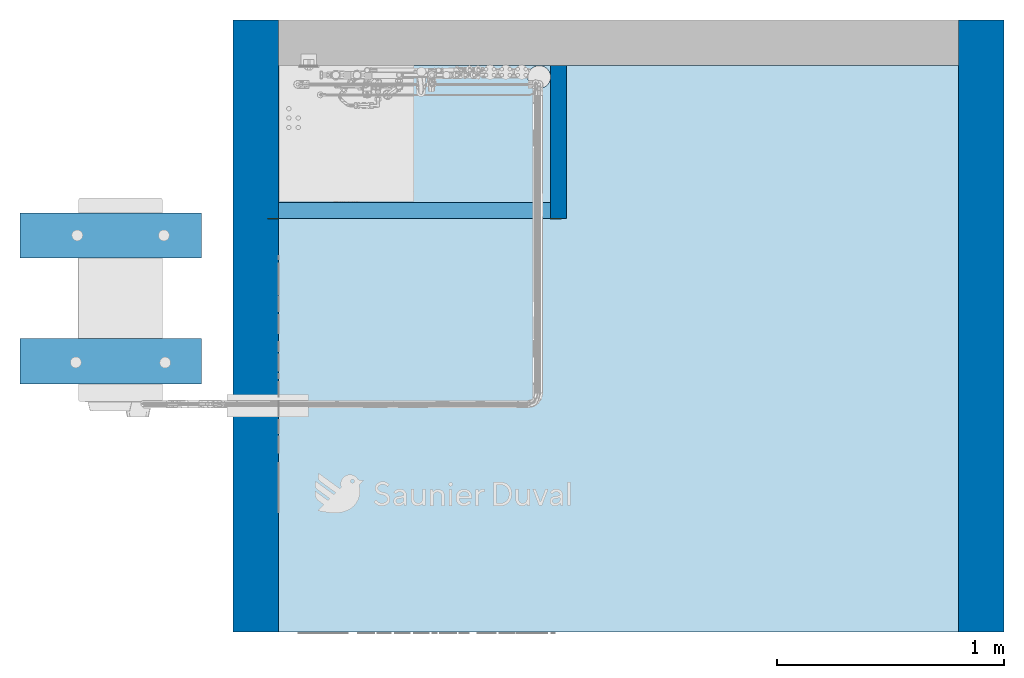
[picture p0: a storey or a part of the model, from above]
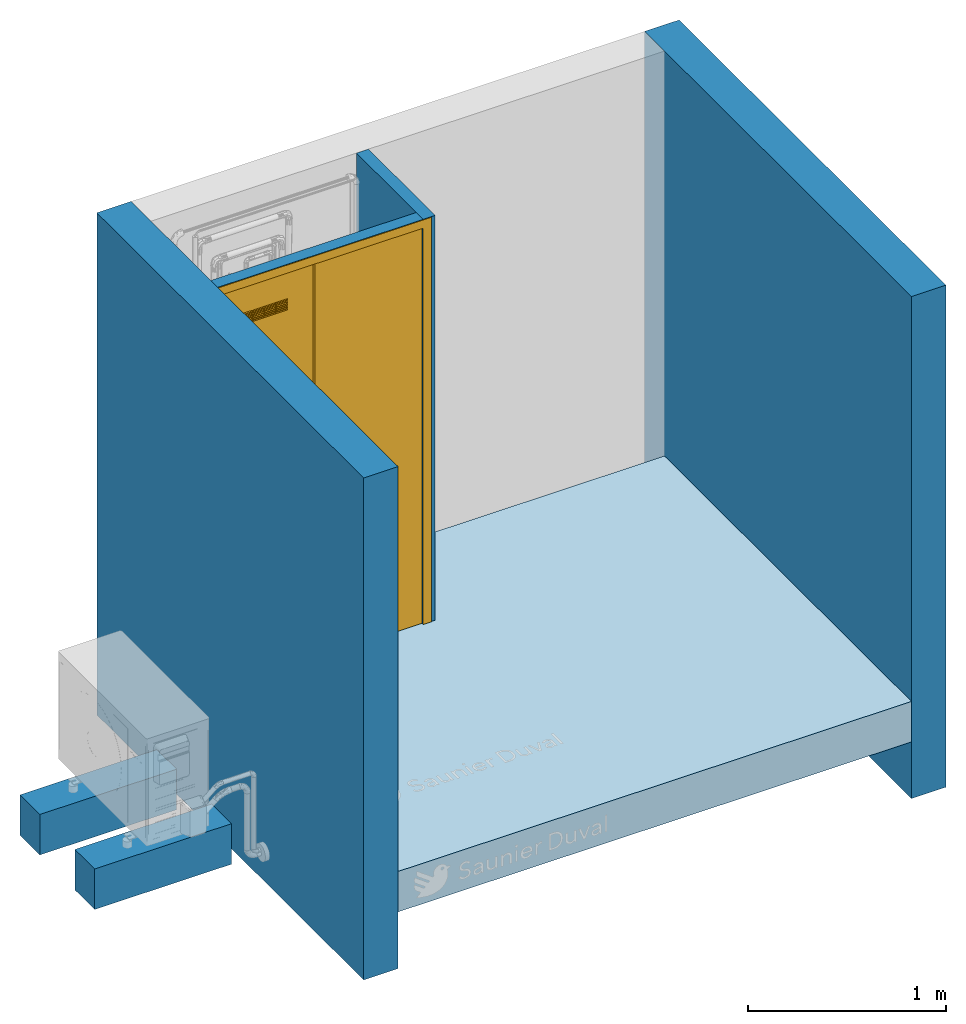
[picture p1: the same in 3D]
Properties of the parts of a building model (IFC2X3)

# File
Description: ViewDefinition [CoordinationView_V2.0], RevitIdentifiers [VersionGUID: d4a8ec76-d9b1-4843-a461-2b5db7719166, NumberOfSaves: 157], CoordinateReference [CoordinateBase: Coordonnées partagées]
File name: 0001
Time: 2024-07-11T17:51:14+01:00
Written by: ODA SDAI 24.6
Made in: Autodesk Revit 24.2.0.63 (FRA) - IFC 24.2.0.63

# IfcProject, 0001
LongName: Salle de formation PAC SD; Phase: Etat du projet

# IfcSite, Default
RefLatitude: 48, 52, 0, 117187; RefLongitude: 2, 19, 59, 880409; RefElevation: 0 m

# IfcBuilding
Pset_BuildingCommon - NumberOfStoreys: 2

# IfcBuildingStorey: Niveau:Ligne du Niveau (3)
Name | LongName | Elevation (m)
Niveau 0 | Niveau 0 | -1.94916e-14
Niveau 1 | Niveau 1 | 2.5
Niveau 2 | Niveau 2 | 6

# IfcBuildingElementProxy: Legrand Boite encastrement batibox 1 poste1:1 poste, Legrand Boite encastrement batibox 1 poste1:1 poste:1151457
In: Niveau 0
Type - Material: Plastique orange
Type - Pset_ManufacturerTypeInformation - Manufacturer: Legrand
Pset_BuildingElementProxyCommon - Reference: 1 poste; sets with these values: 2

# IfcBuildingElementProxy: Legrand Sorties de câbles:Prise courant, Legrand Sorties de câbles:Prise courant:1151456
In: Niveau 0
Type - Material: Plastique, blanc opaque, Plastique, noir opaque
Type - Pset_ManufacturerTypeInformation - Manufacturer: Legrand
Pset_BuildingElementProxyCommon - Reference: Prise courant; sets with these values: 2

# IfcBuildingElementProxy: Legrand plaque2:1 poste, Legrand plaque2:1 poste:1151458
In: Niveau 0
Type - Material: Plastique, blanc opaque
Type - Pset_ManufacturerTypeInformation - Manufacturer: Legrand
Pset_BuildingElementProxyCommon - Reference: 1 poste; sets with these values: 2

# IfcBuildingElementProxy: Legrand support universel-20181:1 poste, Legrand support universel-20181:1 poste:1151459
In: Niveau 0
Type - Material: Plastique, noir opaque
Type - Pset_ManufacturerTypeInformation - Manufacturer: Legrand
Pset_BuildingElementProxyCommon - Reference: 1 poste; sets with these values: 2

# IfcBuildingElementProxy: Logo_Geometry_SD_3Dx10-:Mur_horizontal (2)
In: Niveau 0
Type - Material: Color RGB 251-026-031, Color RGB 10-10-10
Pset_BuildingElementProxyCommon - Reference: Mur_horizontal; sets with these values: 2
Name (Logo_Geometry_SD_3Dx10-:Mur_horizontal:...)
1133916
1393715

# IfcBuildingElementProxy: Logo_Geometry_SD_3Dx10-:Sol, Logo_Geometry_SD_3Dx10-:Sol:1138120
In: Niveau 0
Type - Material: Color RGB 251-026-031, Color RGB 10-10-10
Pset_BuildingElementProxyCommon - Reference: Sol; sets with these values: 2

# IfcBuildingElementProxy: Pied antivibratile ep 40:Pied antivibratile ep 40 (4)
In: Niveau 0
Type - Material: Valeur par défaut Nouveau Matériau
Pset_BuildingElementProxyCommon - Reference: Pied antivibratile ep 40; sets with these values: 2
Name (Pied antivibratile ep 40:Pied antivibratile ep 40:...)
1088830
1088831
1088832
1088833

# IfcBuildingElementProxy: R580F:R580 3/4" x 1/2", R580F:R580 3/4" x 1/2":1107572
In: Niveau 0
Type - Material: Color RGB 169-131-7, Matériau du rendu 255-0-0
Material: <Unnamed>, Color RGB 169-131-7, Matériau du rendu 255-0-0; Group: Alimentation hydraulique 20; Alimentation hydraulique 19; Alimentation hydraulique 26; Alimentation hydraulique 25; Alimentation hydraulique 24; Alimentation hydraulique 23; Alimentation hydraulique 22; Alimentation hydraulique 16; Retour hydraulique 18; Retour hydraulique 17; Retour hydraulique 16; Retour hydraulique 15; Retour hydraulique 13; Retour hydraulique 9
Pset_BuildingElementProxyCommon - Reference: R580 3/4" x 1/2"; sets with these values: 2

# IfcCovering: Isolation des canalisations:Par défaut (32)
Type - PredefinedType: INSULATION
Material: Matériau du rendu 255-255-255
Pset_CoveringCommon - Reference: Par défaut; sets with these values: 2
Name (Isolation des canalisations:Par défaut:...) | In
1118004 | Niveau 0
1118005 | Niveau 0
1118006 | Niveau 0
1118007 | Niveau 0
1118008 | Niveau 0
1118009 | Niveau 0
1118010 | Niveau 0
1118011 | Niveau 1
1118012 | Niveau 0
1118013 | Niveau 1
1118014 | Niveau 0
1118015 | Niveau 0
1118016 | Niveau 0
1118017 | Niveau 1
1118018 | Niveau 1
1118019 | Niveau 1
1118020 | Niveau 0
1118021 | Niveau 1
1118022 | Niveau 0
1118023 | Niveau 0
1118024 | Niveau 0
1118025 | Niveau 0
1118026 | Niveau 0
1118027 | Niveau 0
1118028 | Niveau 0
1118029 | Niveau 0
1118030 | Niveau 0
1118031 | Niveau 0
1118032 | Niveau 0
1118033 | Niveau 0
1118034 | Niveau 0
1118035 | Niveau 0

# IfcDistributionPort (243)
Description: Flow
Name | FlowDirection | Group
OutPort_1088841_3 | SOURCE | Sanitaire 13
Port_1088841_4 | SOURCEANDSINK | Sanitaire 13
Port_1088842_0 | SOURCEANDSINK | Sanitaire 15
Port_1088842_1 | SOURCEANDSINK | Sanitaire 15
InPort_1088856_4 | SINK | Retour hydraulique 11
OutPort_1088861_0 | SOURCE | Retour hydraulique 11
InPort_1088888_1 | SINK | Alimentation hydraulique 15
OutPort_1088856_5 | SOURCE | Alimentation hydraulique 15
Port_1088856_6 | SOURCEANDSINK
InPort_1088861_1 | SINK | Retour hydraulique 11
OutPort_1088863_1 | SOURCE | Retour hydraulique 11
InPort_1088863_2 | SINK | Retour hydraulique 11
OutPort_1088865_0 | SOURCE | Retour hydraulique 11
InPort_1088865_1 | SINK | Retour hydraulique 11
OutPort_1115037_1 | SOURCE | Retour hydraulique 11
InPort_1115321_1 | SINK | Alimentation hydraulique 15
OutPort_1088873_0 | SOURCE | Alimentation hydraulique 15
InPort_1088873_1 | SINK | Alimentation hydraulique 15
OutPort_1088890_1 | SOURCE | Alimentation hydraulique 15
InPort_1088890_2 | SINK | Alimentation hydraulique 15
OutPort_1088888_0 | SOURCE | Alimentation hydraulique 15
Port_1088894_0 | SOURCEANDSINK | Sanitaire 19
Port_1088894_1 | SOURCEANDSINK | Sanitaire 19
Port_1089107_0 | SOURCEANDSINK | Eau Froide Sanitaire 15
Port_1089140_2 | SOURCEANDSINK | Eau Froide Sanitaire 15
Port_1089107_1 | SOURCEANDSINK | Eau Froide Sanitaire 15
Port_1089241_1 | SOURCEANDSINK | Eau Froide Sanitaire 15
Port_1089138_0 | SOURCEANDSINK | Eau Froide Sanitaire 15
Port_1089138_1 | SOURCEANDSINK | Eau Froide Sanitaire 15
Port_1089140_1 | SOURCEANDSINK | Eau Froide Sanitaire 15
Port_1089239_0 | SOURCEANDSINK | Eau Froide Sanitaire 15
Port_1089241_2 | SOURCEANDSINK | Eau Froide Sanitaire 15
Port_1089239_1 | SOURCEANDSINK | Eau Froide Sanitaire 15
Port_1101598_1 | SOURCEANDSINK | Eau Froide Sanitaire 15
InPort_1089401_0 | SINK | Eau Chaude Sanitaire 6
InPort_1089420_1 | SINK | Eau Chaude Sanitaire 6
OutPort_1089401_1 | SOURCE | Eau Chaude Sanitaire 6
InPort_1089414_0 | SINK | Eau Chaude Sanitaire 6
OutPort_1089420_2 | SOURCE | Eau Chaude Sanitaire 6
InPort_1089440_1 | SINK | Eau Chaude Sanitaire 6
OutPort_1089414_1 | SOURCE | Eau Chaude Sanitaire 6
InPort_1104246_0 | SINK | Eau Chaude Sanitaire 6
OutPort_1089440_2 | SOURCE | Eau Chaude Sanitaire 6
OutPort_1089474_0 | SOURCE | Alimentation hydraulique 20
InPort_1089474_1 | SINK | Alimentation hydraulique 20
OutPort_1089503_1 | SOURCE | Alimentation hydraulique 20
InPort_1089503_2 | SINK | Alimentation hydraulique 20
OutPort_1089497_0 | SOURCE | Alimentation hydraulique 20
InPort_1089497_1 | SINK | Alimentation hydraulique 20
OutPort_1108240_1 | SOURCE | Alimentation hydraulique 20
InPort_1108240_2 | SINK | Alimentation hydraulique 20
OutPort_1089513_0 | SOURCE | Alimentation hydraulique 20
InPort_1089513_1 | SINK | Alimentation hydraulique 20
OutPort_1108242_2 | SOURCE | Alimentation hydraulique 20
OutPort_1089553_0 | SOURCE | Retour hydraulique 14
InPort_1089553_1 | SINK | Retour hydraulique 14
OutPort_1089572_1 | SOURCE | Retour hydraulique 14
InPort_1089572_2 | SINK | Retour hydraulique 14
OutPort_1089566_0 | SOURCE | Retour hydraulique 14
InPort_1089566_1 | SINK | Retour hydraulique 14
OutPort_1108389_1 | SOURCE | Retour hydraulique 14
OutPort_1098783_2 | SOURCE
InPort_1098783_5 | SINK | Eau Froide Sanitaire 15
OutPort_1099300_2 | SOURCE | Eau Froide Sanitaire 15
InPort_1099504_0 | SINK | Eau Froide Sanitaire 16
OutPort_1098783_6 | SOURCE | Eau Froide Sanitaire 16
InPort_1099460_0 | SINK | Eau Froide Sanitaire 14
OutPort_1098783_7 | SOURCE | Eau Froide Sanitaire 14
InPort_1099562_0 | SINK | Eau Froide Sanitaire 17
OutPort_1098783_8 | SOURCE | Eau Froide Sanitaire 17
InPort_1099265_0 | SINK | Eau Froide Sanitaire 15
OutPort_1101598_2 | SOURCE | Eau Froide Sanitaire 15
InPort_1099300_1 | SINK | Eau Froide Sanitaire 15
OutPort_1099265_1 | SOURCE | Eau Froide Sanitaire 15
OutPort_1099460_1 | SOURCE | Eau Froide Sanitaire 14
OutPort_1099504_1 | SOURCE | Eau Froide Sanitaire 16
OutPort_1099562_1 | SOURCE | Eau Froide Sanitaire 17
OutPort_1099806_2 | SOURCE
InPort_1099806_5 | SINK | Eau Chaude Sanitaire 6
OutPort_1104268_1 | SOURCE | Eau Chaude Sanitaire 6
OutPort_1099806_6 | SOURCE
InPort_1100829_0 | SINK | Eau Chaude Sanitaire 4
OutPort_1099806_7 | SOURCE | Eau Chaude Sanitaire 4
InPort_1100867_0 | SINK | Eau Chaude Sanitaire 7
OutPort_1099806_8 | SOURCE | Eau Chaude Sanitaire 7
OutPort_1100829_1 | SOURCE | Eau Chaude Sanitaire 4
OutPort_1100867_1 | SOURCE | Eau Chaude Sanitaire 7
InPort_1101598_3 | SINK | Eau Froide Sanitaire 15
OutPort_1102837_0 | SOURCE | Eau Froide Sanitaire 15
InPort_1102572_1 | SINK | Eau Froide Sanitaire 15
OutPort_1101707_0 | SOURCE | Eau Froide Sanitaire 15
InPort_1101707_1 | SINK | Eau Froide Sanitaire 15
InPort_1102590_1 | SINK | Eau Froide Sanitaire 15
OutPort_1102572_2 | SOURCE | Eau Froide Sanitaire 15
InPort_1102797_1 | SINK | Eau Froide Sanitaire 15
OutPort_1102590_0 | SOURCE | Eau Froide Sanitaire 15
InPort_1102837_1 | SINK | Eau Froide Sanitaire 15
OutPort_1102797_2 | SOURCE | Eau Froide Sanitaire 15
InPort_1104285_1 | SINK | Eau Chaude Sanitaire 6
OutPort_1104246_1 | SOURCE | Eau Chaude Sanitaire 6
InPort_1104268_2 | SINK | Eau Chaude Sanitaire 6
OutPort_1104256_0 | SOURCE | Eau Chaude Sanitaire 6
InPort_1104256_1 | SINK | Eau Chaude Sanitaire 6
OutPort_1104285_2 | SOURCE | Eau Chaude Sanitaire 6
InPort_1107572_1 | SINK | Alimentation hydraulique 19
OutPort_1108148_1 | SOURCE | Alimentation hydraulique 19
InPort_1108068_1 | SINK | Alimentation hydraulique 20
OutPort_1107572_2 | SOURCE | Alimentation hydraulique 20
InPort_1109853_0 | SINK | Alimentation hydraulique 26
OutPort_1107572_3 | SOURCE | Alimentation hydraulique 26
InPort_1109774_0 | SINK | Alimentation hydraulique 25
OutPort_1107572_4 | SOURCE | Alimentation hydraulique 25
InPort_1109692_0 | SINK | Alimentation hydraulique 24
OutPort_1107572_5 | SOURCE | Alimentation hydraulique 24
InPort_1109607_0 | SINK | Alimentation hydraulique 23
OutPort_1107572_6 | SOURCE | Alimentation hydraulique 23
InPort_1109531_0 | SINK | Alimentation hydraulique 22
OutPort_1107572_7 | SOURCE | Alimentation hydraulique 22
InPort_1109451_0 | SINK | Alimentation hydraulique 16
OutPort_1107572_8 | SOURCE | Alimentation hydraulique 16
InPort_1107572_9 | SINK | Retour hydraulique 18
OutPort_1109369_0 | SOURCE | Retour hydraulique 18
InPort_1107572_10 | SINK | Retour hydraulique 17
OutPort_1109291_0 | SOURCE | Retour hydraulique 17
InPort_1107572_11 | SINK | Retour hydraulique 16
OutPort_1109175_0 | SOURCE | Retour hydraulique 16
InPort_1107572_12 | SINK | Retour hydraulique 15
OutPort_1109048_0 | SOURCE | Retour hydraulique 15
InPort_1107572_13 | SINK | Retour hydraulique 13
OutPort_1108907_0 | SOURCE | Retour hydraulique 13
InPort_1107572_14 | SINK | Retour hydraulique 9
OutPort_1108758_0 | SOURCE | Retour hydraulique 9
InPort_1108389_2 | SINK | Retour hydraulique 14
OutPort_1108037_0 | SOURCE | Retour hydraulique 14
InPort_1108037_1 | SINK | Retour hydraulique 14
OutPort_1108391_2 | SOURCE | Retour hydraulique 14
InPort_1108058_0 | SINK | Alimentation hydraulique 20
OutPort_1108068_2 | SOURCE | Alimentation hydraulique 20
InPort_1108242_1 | SINK | Alimentation hydraulique 20
OutPort_1108058_1 | SOURCE | Alimentation hydraulique 20
InPort_1108148_1 | SINK | Alimentation hydraulique 19
OutPort_1107572_1 | SOURCE | Alimentation hydraulique 19
InPort_1108306_0 | SINK | Alimentation hydraulique 19
OutPort_1108148_2 | SOURCE | Alimentation hydraulique 19
InPort_1108391_1 | SINK | Retour hydraulique 14
OutPort_1108306_1 | SOURCE | Retour hydraulique 14
InPort_1108758_1 | SINK | Retour hydraulique 9
InPort_1108907_1 | SINK | Retour hydraulique 13
InPort_1109048_1 | SINK | Retour hydraulique 15
InPort_1109175_1 | SINK | Retour hydraulique 16
InPort_1109291_1 | SINK | Retour hydraulique 17
InPort_1109369_1 | SINK | Retour hydraulique 18
OutPort_1109451_1 | SOURCE | Alimentation hydraulique 16
OutPort_1109531_1 | SOURCE | Alimentation hydraulique 22
OutPort_1109607_1 | SOURCE | Alimentation hydraulique 23
OutPort_1109692_1 | SOURCE | Alimentation hydraulique 24
OutPort_1109774_1 | SOURCE | Alimentation hydraulique 25
OutPort_1109853_1 | SOURCE | Alimentation hydraulique 26
Port_1110453_0 | SOURCEANDSINK | Alimentation hydraulique 27
Port_1110453_1 | SOURCEANDSINK | Alimentation hydraulique 27
InPort_1114524_0 | SINK | Alimentation hydraulique 21
InPort_1114792_1 | SINK | Alimentation hydraulique 21
OutPort_1114524_1 | SOURCE | Alimentation hydraulique 21
InPort_1114532_0 | SINK | Alimentation hydraulique 21
OutPort_1114792_2 | SOURCE | Alimentation hydraulique 21
InPort_1114834_1 | SINK | Alimentation hydraulique 21
OutPort_1114532_1 | SOURCE | Alimentation hydraulique 21
OutPort_1114585_0 | SOURCE | Sanitaire 17
InPort_1114585_1 | SINK | Sanitaire 17
OutPort_1114601_1 | SOURCE | Sanitaire 17
InPort_1114601_2 | SINK | Sanitaire 17
OutPort_1114595_0 | SOURCE | Sanitaire 17
InPort_1114595_1 | SINK | Alimentation hydraulique 15
OutPort_1114614_1 | SOURCE | Alimentation hydraulique 15
InPort_1114614_2 | SINK | Alimentation hydraulique 15
OutPort_1114606_0 | SOURCE | Alimentation hydraulique 15
InPort_1114606_1 | SINK | Alimentation hydraulique 15
OutPort_1115197_1 | SOURCE | Alimentation hydraulique 15
InPort_1114860_0 | SINK | Alimentation hydraulique 21
OutPort_1114834_2 | SOURCE | Alimentation hydraulique 21
InPort_1114878_1 | SINK | Alimentation hydraulique 21
OutPort_1114860_1 | SOURCE | Alimentation hydraulique 21
InPort_1114870_0 | SINK | Alimentation hydraulique 21
OutPort_1114878_2 | SOURCE | Alimentation hydraulique 21
InPort_1114887_1 | SINK | Alimentation hydraulique 21
OutPort_1114870_1 | SOURCE | Alimentation hydraulique 21
InPort_1114881_0 | SINK | Alimentation hydraulique 21
OutPort_1114887_2 | SOURCE | Alimentation hydraulique 21
InPort_1115096_2 | SINK | Alimentation hydraulique 21
OutPort_1114881_1 | SOURCE | Alimentation hydraulique 21
InPort_1115037_2 | SINK | Retour hydraulique 11
OutPort_1115029_0 | SOURCE | Retour hydraulique 11
InPort_1115029_1 | SINK | Alimentation hydraulique 21
OutPort_1115098_1 | SOURCE | Alimentation hydraulique 21
InPort_1115042_0 | SINK | Alimentation hydraulique 21
OutPort_1115096_1 | SOURCE | Alimentation hydraulique 21
InPort_1115098_2 | SINK | Alimentation hydraulique 21
OutPort_1115042_1 | SOURCE | Alimentation hydraulique 21
InPort_1115197_2 | SINK | Alimentation hydraulique 15
OutPort_1115185_0 | SOURCE | Alimentation hydraulique 15
InPort_1115185_1 | SINK | Alimentation hydraulique 15
OutPort_1115335_2 | SOURCE | Alimentation hydraulique 15
InPort_1115223_0 | SINK | Alimentation hydraulique 15
OutPort_1115331_2 | SOURCE | Alimentation hydraulique 15
InPort_1115335_1 | SINK | Alimentation hydraulique 15
OutPort_1115223_1 | SOURCE | Alimentation hydraulique 15
InPort_1115310_0 | SINK | Alimentation hydraulique 15
OutPort_1115321_2 | SOURCE | Alimentation hydraulique 15
InPort_1115331_1 | SINK | Alimentation hydraulique 15
OutPort_1115310_1 | SOURCE | Alimentation hydraulique 15
Port_1115904_0 | SOURCEANDSINK | Alimentation hydraulique 28
Port_1115904_1 | SOURCEANDSINK | Alimentation hydraulique 28
Port_1117079_0 | SOURCEANDSINK | Alimentation hydraulique 29
Port_1117079_1 | SOURCEANDSINK | Alimentation hydraulique 29
Port_1117090_0 | SOURCEANDSINK | Alimentation hydraulique 30
Port_1117090_1 | SOURCEANDSINK | Alimentation hydraulique 30
Port_1117101_0 | SOURCEANDSINK | Alimentation hydraulique 31
Port_1117101_1 | SOURCEANDSINK | Alimentation hydraulique 31
Port_1117112_0 | SOURCEANDSINK | Alimentation hydraulique 32
Port_1117112_1 | SOURCEANDSINK | Alimentation hydraulique 32
Port_1117125_0 | SOURCEANDSINK | Alimentation hydraulique 33
Port_1117125_1 | SOURCEANDSINK | Alimentation hydraulique 33
Port_1117146_0 | SOURCEANDSINK | Alimentation hydraulique 34
Port_1117146_1 | SOURCEANDSINK | Alimentation hydraulique 34
Port_1117281_0 | SOURCEANDSINK | Alimentation hydraulique 35
Port_1117281_1 | SOURCEANDSINK | Alimentation hydraulique 35
Port_1117298_0 | SOURCEANDSINK | Alimentation hydraulique 36
Port_1117298_1 | SOURCEANDSINK | Alimentation hydraulique 36
Port_1117587_0 | SOURCEANDSINK | Alimentation hydraulique 37
Port_1117587_1 | SOURCEANDSINK | Alimentation hydraulique 37
InPort_1120506_10 | SINK
OutPort_1120506_11 | SOURCE
OutPort_1120506_16 | SOURCE
OutPort_1120506_17 | SOURCE
InPort_1120506_18 | SINK
OutPort_1120506_19 | SOURCE
InPort_1120506_20 | SINK
OutPort_1120506_21 | SOURCE
InPort_1120506_22 | SINK
InPort_1120506_23 | SINK
OutPort_1120506_24 | SOURCE
OutPort_1120506_25 | SOURCE
Port_1120506_26 | SOURCEANDSINK

# IfcDoor: Placard coulissante - 2 panneaux_GM:Placard coulissante - 2 panneaux 2.50, Placard coulissante - 2 panneaux_GM:Placard coulissante - 2 panneaux 2.50:1122378
In: Niveau 0
Type - OperationType: SLIDING_TO_RIGHT; ParameterTakesPrecedence: no; Sizeable: no; Material: Plastique, blanc opaque, Verre, vitrage transparent
Type - Placard coulissante - 2 panneaux_GM:Placard coulissante - 2 panneaux 2.50:1122378:1 - PanelOperation: SLIDING
Type - Pset_DoorCommon - IsExternal: no; ThermalTransmittance: 3.7021 kg/K/s3
OverallHeight: 2.45 m; OverallWidth: 1.2 m
Pset_DoorCommon - Reference: Placard coulissante - 2 panneaux 2.50
Pset_QuantityTakeOff - Reference: Placard coulissante - 2 panneaux 2.50

# IfcFlowController: HC_Manifold_MEPcontent_Valsir_Pexal BRASS_3 Way Cold Water_INT-EN:1/2'' x 3/4'', HC_Manifold_MEPcontent_Valsir_Pexal BRASS_3 Way Cold Water_INT-EN:1/2'' x 3/4'':1098783
In: Niveau 0
Type - Material: Color RGB 202-154-058
Type - Pset_ElementShading - Color: Color RGB 202-154-058
Type - Pset_ManufacturerTypeInformation - Manufacturer: Valsir S.p.A.
Classification: SfB]53 (Default Classification); Group: Eau Froide Sanitaire 15; Eau Froide Sanitaire 16; Eau Froide Sanitaire 14; Eau Froide Sanitaire 17
Pset_DistributionFlowElementCommon - Reference: 1/2'' x 3/4''; sets with these values: 2

# IfcFlowController: HC_Manifold_MEPcontent_Valsir_Pexal BRASS_3 Way Hot Water_INT-EN:1/2'' x 3/4'', HC_Manifold_MEPcontent_Valsir_Pexal BRASS_3 Way Hot Water_INT-EN:1/2'' x 3/4'':1099806
In: Niveau 0
Type - Material: Color RGB 202-154-058
Type - Pset_ElementShading - Color: Color RGB 202-154-058
Type - Pset_ManufacturerTypeInformation - Manufacturer: Valsir S.p.A.
Classification: SfB]53 (Default Classification); Group: Eau Chaude Sanitaire 6; Eau Chaude Sanitaire 4; Eau Chaude Sanitaire 7
Pset_DistributionFlowElementCommon - Reference: 1/2'' x 3/4''; sets with these values: 2

# IfcFlowController: M_Valve_Ball_MEPcontent_Caleffi_327 DN20:3/4'', M_Valve_Ball_MEPcontent_Caleffi_327 DN20:3/4'':1102572
In: Niveau 0
Type - PredefinedType: REGULATING; Material: Color RGB 187-001-001, Color RGB 202-154-058, Color RGB 045-045-045
Type - Pset_DuctConnection - ConnectionType: Gas ISO 228/1
Type - Pset_ManufacturerTypeInformation - Manufacturer: Caleffi Italy
Type - Pset_PipeConnection - ConnectionType: Gas ISO 228/1
Material: Color RGB 045-045-045, Color RGB 202-154-058, Color RGB 187-001-001; Group: Eau Froide Sanitaire 15
Pset_DistributionFlowElementCommon - Reference: 3/4''; sets with these values: 2

# IfcFlowController: Plumbing_Valves_Caleffi_Pressure_ Reducing_ Valve-533HA-DN15_DN20:533340HA, Plumbing_Valves_Caleffi_Pressure_ Reducing_ Valve-533HA-DN15_DN20:533340HA:1102797
In: Niveau 0
Type - Material: Metal - Caleffi - Brass, Technopolymer - Caleffi - Black, Technopolymer - Caleffi - Grey
Type - Pset_DuctConnection - ConnectionType: NPT
Type - Pset_ManufacturerTypeInformation - Manufacturer: Caleffi North America, Inc.
Type - Pset_PipeConnection - ConnectionType: NPT
Classification: D3040 Uniformat (Uniformat); Group: Eau Froide Sanitaire 15
Pset_DistributionFlowElementCommon - Reference: 533340HA; sets with these values: 2

# IfcFlowController: Siphon 32:Siphon 32, Siphon 32:Siphon 32:1088841
In: Niveau 0
Type - Material: <Unnamed>
Type - Pset_ManufacturerTypeInformation - Manufacturer: GIRPI
Pset_DistributionFlowElementCommon - Reference: Siphon 32; sets with these values: 2
Group: Sanitaire 13

# IfcFlowFitting: COMAP - SKINPRESS ppsu - Coude_45_90_9041W_9090W:Coude_45_90_9041W_9090W (11)
In: Niveau 0
Type - Material: PPSU, Bague blanche VisuControl, Inox
Type - Pset_ManufacturerTypeInformation - Manufacturer: COMAP
Pset_DistributionFlowElementCommon - Reference: Coude_45_90_9041W_9090W; sets with these values: 2
Name (COMAP - SKINPRESS ppsu - Coude_45_90_9041W_9090W:Coude_45_90_9041W_9090W:...) | Group | Material
1089140 | Eau Froide Sanitaire 15
1089241 | Eau Froide Sanitaire 15 | Bague blanche VisuControl, Inox, PPSU
1089420 | Eau Chaude Sanitaire 6 | Bague blanche VisuControl, Inox, PPSU
1089440 | Eau Chaude Sanitaire 6 | Bague blanche VisuControl, Inox, PPSU
1089503 | Alimentation hydraulique 20
1089572 | Retour hydraulique 14 | Bague blanche VisuControl, Inox, PPSU
1104285 | Eau Chaude Sanitaire 6 | Bague blanche VisuControl, Inox, PPSU
1108240 | Alimentation hydraulique 20 | Bague blanche VisuControl, Inox, PPSU
1108242 | Alimentation hydraulique 20 | Bague blanche VisuControl, Inox, PPSU
1108389 | Retour hydraulique 14 | Bague blanche VisuControl, Inox, PPSU
1108391 | Retour hydraulique 14 | Bague blanche VisuControl, Inox, PPSU

# IfcFlowFitting: COMAP - SKINPRESS ppsu - Manchon_Réduit_9240W:Manchon_Réduit_9240W (4)
In: Niveau 0
Type - Material: Bague blanche VisuControl, Inox, PPSU
Type - Pset_ManufacturerTypeInformation - Manufacturer: COMAP
Pset_DistributionFlowElementCommon - Reference: Manchon_Réduit_9240W; sets with these values: 2
Name (COMAP - SKINPRESS ppsu - Manchon_Réduit_9240W:Manchon_Réduit_9240W:...) | Group
1099300 | Eau Froide Sanitaire 15
1104268 | Eau Chaude Sanitaire 6
1108068 | Alimentation hydraulique 20
1108148 | Alimentation hydraulique 19

# IfcFlowFitting: COMAP - SKINPRESS ppsu - Té_égal_réduit_9130W_9130RW:Standard, COMAP - SKINPRESS ppsu - Té_égal_réduit_9130W_9130RW:Standard:1101598
In: Niveau 0
Type - Material: Bague blanche VisuControl, Inox, PPSU
Type - Pset_ManufacturerTypeInformation - Manufacturer: COMAP
Pset_DistributionFlowElementCommon - Reference: Standard; sets with these values: 2
Group: Eau Froide Sanitaire 15

# IfcFlowFitting: Coude - tube frigo:Standard (15)
In: Niveau 0
Type - Material: Cuivre
Pset_DistributionFlowElementCommon - Reference: Standard; sets with these values: 2
Name (Coude - tube frigo:Standard:...) | Group
1088863 | Retour hydraulique 11
1088890 | Alimentation hydraulique 15
1114601 | Sanitaire 17
1114614 | Alimentation hydraulique 15
1114792 | Alimentation hydraulique 21
1114834 | Alimentation hydraulique 21
1114878 | Alimentation hydraulique 21
1114887 | Alimentation hydraulique 21
1115037 | Retour hydraulique 11
1115096 | Alimentation hydraulique 21
1115098 | Alimentation hydraulique 21
1115197 | Alimentation hydraulique 15
1115321 | Alimentation hydraulique 15
1115331 | Alimentation hydraulique 15
1115335 | Alimentation hydraulique 15

# IfcFlowFitting: SA_Connection Piece_MEPcontent_Valsir_Pexal BRASS_Kit with Nut_Shared:14 mm x 2 mm-1/2'' (6)
In: Niveau 0
Type - Material: Color RGB 202-154-058
Type - Pset_ElementShading - Color: Color RGB 202-154-058
Type - Pset_FlowFittingDuctFitting - Color: Color RGB 202-154-058
Type - Pset_FlowFittingPipeFitting - Color: Color RGB 202-154-058
Type - Pset_ManufacturerTypeInformation - Manufacturer: Valsir S.p.A.
Classification: SfB]53 (Default Classification)
Pset_DistributionFlowElementCommon - Reference: 14 mm x 2 mm-1/2''; sets with these values: 2
Name (SA_Connection Piece_MEPcontent_Valsir_Pexal BRASS_Kit with Nut_Shared:14 mm x 2 mm-1/2'':...)
1098784
1098785
1098786
1099807
1099808
1099809

# IfcFlowMovingDevice: HC_Heat Pump_GM_Saunier Duval_GeniaSet TEK_IS_kit complet+2C:HA 10-7_2 STB, HC_Heat Pump_GM_Saunier Duval_GeniaSet TEK_IS_kit complet+2C:HA 10-7_2 STB:1120506
In: Niveau 0
Type - Material: Color RGB 121-121-121, Color RGB 244-244-244, Color RGB 116-051-029, Color RGB 040-040-040, Color RGB 251-026-031, Color RGB 191-153-066
Type - Pset_ManufacturerTypeInformation - Manufacturer: Saunier Duval
Material: Color RGB 191-153-066, Color RGB 040-040-040, Color RGB 000-000-255, Color RGB 116-051-029, <Unnamed>, Color RGB 120-120-120, Color RGB 251-026-031, Color RGB 121-121-121, Color RGB 244-244-244
Pset_DistributionFlowElementCommon - Reference: HA 10-7_2 STB; sets with these values: 2

# IfcFlowMovingDevice: HC_Heat Pump_MEPcontent_Saunier Duval_GeniaAir TEK_HA 4-6_FR-FR:HA 4-7_2 OS 230V B3, HC_Heat Pump_MEPcontent_Saunier Duval_GeniaAir TEK_HA 4-6_FR-FR:HA 4-7_2 OS 230V B3:1088856
In: Niveau 0
Type - Material: Color RGB 040-040-040, Color RGB 251-026-031, Color RGB 235-235-235, Color RGB 190-190-190, Color RGB 174-174-174
Type - Pset_ManufacturerTypeInformation - Manufacturer: Saunier Duval
Pset_DistributionFlowElementCommon - Reference: HA 4-7_2 OS 230V B3; sets with these values: 2
Group: Retour hydraulique 11; Alimentation hydraulique 15

# IfcFlowSegment: Canalisation souple arrondie:Souple - Circulaire, Canalisation souple arrondie:Souple - Circulaire:1088894
In: Niveau 0
Type - PredefinedType: FLEXIBLESEGMENT
Pset_DistributionFlowElementCommon - Reference: Souple - Circulaire; sets with these values: 2
Group: Sanitaire 19

# IfcFlowSegment: Canalisation:COMAP MULTISKIN - SKINPRESS PPSU (24)
In: Niveau 0
Type - Pset_ManufacturerTypeInformation - Manufacturer: COMAP
Pset_DistributionFlowElementCommon - Reference: COMAP MULTISKIN - SKINPRESS PPSU; sets with these values: 2
Pset_FlowSegmentDuctSegment - sets with these values: 2
Name (Canalisation:COMAP MULTISKIN - SKINPRESS PPSU:...) | Length (m) | Group
1089107 | 0.105 | Eau Froide Sanitaire 15
1089138 | 0.0634913 | Eau Froide Sanitaire 15
1089239 | 1.76 | Eau Froide Sanitaire 15
1089401 | 0.1475 | Eau Chaude Sanitaire 6
1089414 | 0.275 | Eau Chaude Sanitaire 6
1089474 | 0.101544 | Alimentation hydraulique 20
1089497 | 0.319 | Alimentation hydraulique 20
1089513 | 1.61979 | Alimentation hydraulique 20
1089553 | 0.247 | Retour hydraulique 14
1089566 | 0.4515 | Retour hydraulique 14
1099265 | 0.0579708 | Eau Froide Sanitaire 15
1099460 | 0.6016 | Eau Froide Sanitaire 14
1099504 | 0.6016 | Eau Froide Sanitaire 16
1099562 | 0.6 | Eau Froide Sanitaire 17
1100829 | 0.6516 | Eau Chaude Sanitaire 4
1100867 | 0.65 | Eau Chaude Sanitaire 7
1101707 | 0.353 | Eau Froide Sanitaire 15
1102590 | 0.02975 | Eau Froide Sanitaire 15
1102837 | 0.05325 | Eau Froide Sanitaire 15
1104246 | 1.74141 | Eau Chaude Sanitaire 6
1104256 | 0.0478441 | Eau Chaude Sanitaire 6
1108037 | 1.64869 | Retour hydraulique 14
1108058 | 0.1005 | Alimentation hydraulique 20
1108306 | 0.061 | Retour hydraulique 14; Alimentation hydraulique 19

# IfcFlowSegment: Canalisation:Cuivre Frigo (17)
In: Niveau 0
Pset_DistributionFlowElementCommon - Reference: Cuivre Frigo; sets with these values: 2
Pset_FlowSegmentDuctSegment - sets with these values: 2
Name (Canalisation:Cuivre Frigo:...) | Length (m) | Group
1088861 | 0.1455 | Retour hydraulique 11
1088865 | 0.159449 | Retour hydraulique 11
1088873 | 0.0496756 | Alimentation hydraulique 15
1088888 | 0.137924 | Alimentation hydraulique 15
1114524 | 0.4909 | Alimentation hydraulique 21
1114532 | 0.9018 | Alimentation hydraulique 21
1114585 | 0.440138 | Sanitaire 17
1114595 | 0.9664 | Alimentation hydraulique 15; Sanitaire 17
1114606 | 2.75084 | Alimentation hydraulique 15
1114860 | 0.0043 | Alimentation hydraulique 21
1114870 | 2.7968 | Alimentation hydraulique 21
1114881 | 1.36677 | Alimentation hydraulique 21
1115029 | 0.445144 | Retour hydraulique 11; Alimentation hydraulique 21
1115042 | 1.34742 | Alimentation hydraulique 21
1115185 | 1.31187 | Alimentation hydraulique 15
1115223 | 1.35145 | Alimentation hydraulique 15
1115310 | 0.352103 | Alimentation hydraulique 15

# IfcFlowSegment: Canalisation:PER Bleu (6)
In: Niveau 0
Pset_DistributionFlowElementCommon - Reference: PER Bleu; sets with these values: 2
Pset_FlowSegmentDuctSegment - sets with these values: 2
Name (Canalisation:PER Bleu:...) | Length (m) | Group
1108758 | 0.596336 | Retour hydraulique 9
1108907 | 0.595 | Retour hydraulique 13
1109048 | 0.595 | Retour hydraulique 15
1109175 | 0.596336 | Retour hydraulique 16
1109291 | 0.596336 | Retour hydraulique 17
1109369 | 0.596336 | Retour hydraulique 18

# IfcFlowSegment: Canalisation:PER Rouge (6)
In: Niveau 0
Pset_DistributionFlowElementCommon - Reference: PER Rouge; sets with these values: 2
Pset_FlowSegmentDuctSegment - sets with these values: 2
Name (Canalisation:PER Rouge:...) | Length (m) | Group
1109451 | 0.577034 | Alimentation hydraulique 16
1109531 | 0.577034 | Alimentation hydraulique 22
1109607 | 0.595606 | Alimentation hydraulique 23
1109692 | 0.595606 | Alimentation hydraulique 24
1109774 | 0.595606 | Alimentation hydraulique 25
1109853 | 0.595606 | Alimentation hydraulique 26

# IfcFlowSegment: Canalisation:PVC - NF (12)
In: Niveau 0
Pset_DistributionFlowElementCommon - Reference: PVC - NF; sets with these values: 2
Pset_FlowSegmentDuctSegment - sets with these values: 2
Name (Canalisation:PVC - NF:...) | Length (m) | Group
1088842 | 0.35 | Sanitaire 15
1110453 | 0.365 | Alimentation hydraulique 27
1115904 | 0.368153 | Alimentation hydraulique 28
1117079 | 0.368153 | Alimentation hydraulique 29
1117090 | 0.368153 | Alimentation hydraulique 30
1117101 | 0.368153 | Alimentation hydraulique 31
1117112 | 0.368153 | Alimentation hydraulique 32
1117125 | 0.368153 | Alimentation hydraulique 33
1117146 | 0.368153 | Alimentation hydraulique 34
1117281 | 0.368153 | Alimentation hydraulique 35
1117298 | 0.368153 | Alimentation hydraulique 36
1117587 | 0.36 | Alimentation hydraulique 37

# IfcOpeningElement: Opening (4)
In: Niveau 0
Name | Reference | sets with these values
Mur de base:Générique - Ext. 200 mm:1088777 | Placard coulissante - 2 panneaux 2.50 | 2
Sol:Dalle en béton - 250 mm:634 | Dalle en béton - 250 mm | 2
Mur de base:Générique - Int. 70 mm:1088855 | Placard coulissante - 2 panneaux 2.50 | 2
Placard coulissante - 2 panneaux_GM:Placard coulissante - 2 panneaux 2.50:1122378:1

# IfcOpeningElement: Recess, Mur de base:Générique - Ext. 200 mm:1114462
In: Niveau 0
Pset_OpeningElementCommon - Reference: 1 poste; sets with these values: 2

# IfcSlab: Sol:Dalle en béton - 250 mm (3)
In: Niveau 0
Type - PredefinedType: FLOOR; Material: Maçonnerie - Béton 0.25 m
Type - Pset_SlabCommon - IsExternal: no
Pset_QuantityTakeOff - Reference: Dalle en béton - 250 mm; sets with these values: 2
Pset_SlabCommon - Reference: Dalle en béton - 250 mm; PitchAngle: 0 deg
Name (Sol:Dalle en béton - 250 mm:...) | LoadBearing
1088780 | yes
1088836 | no
1088850 | no

# IfcWallStandardCase: Mur de base:Générique - Ext. 200 mm (3)
In: Niveau 0
Type - PredefinedType: STANDARD; Material: Mur par défaut 0.2 m, Color RGB 255-255-255 0.001 m
Type - Pset_WallCommon - IsExternal: yes
Pset_QuantityTakeOff - Reference: Générique - Ext. 200 mm; sets with these values: 2
Pset_WallCommon - Reference: Générique - Ext. 200 mm; ExtendToStructure: no; LoadBearing: yes
Name (Mur de base:Générique - Ext. 200 mm:...)
1088775
1088777
1114462

# IfcWallStandardCase: Mur de base:Générique - Int. 70 mm, Mur de base:Générique - Int. 70 mm:1088855
In: Niveau 0
Type - PredefinedType: STANDARD; Material: Mur par défaut 0.07 m
Type - Pset_WallCommon - IsExternal: no
Pset_QuantityTakeOff - Reference: Générique - Int. 70 mm; sets with these values: 2
Pset_WallCommon - ExtendToStructure: no; LoadBearing: no; Reference: Générique - Int. 70 mm

# IfcWallStandardCase: Mur de base:Int. Platre 70 mm, Mur de base:Int. Platre 70 mm:1122245
In: Niveau 0
Type - PredefinedType: STANDARD; Material: PVC - Blanc 0.07 m
Type - Pset_WallCommon - IsExternal: no
Pset_QuantityTakeOff - Reference: Int. Platre 70 mm; sets with these values: 2
Pset_WallCommon - ExtendToStructure: no; LoadBearing: no; Reference: Int. Platre 70 mm
